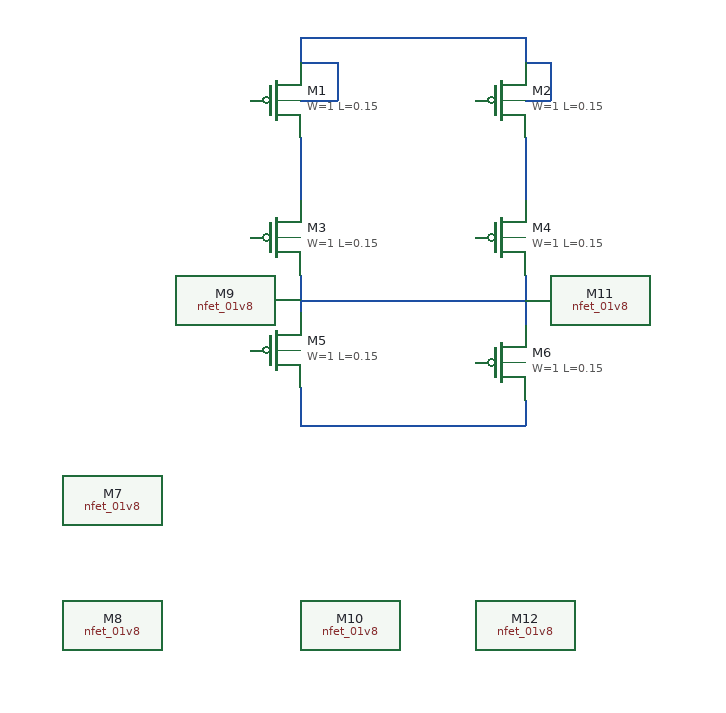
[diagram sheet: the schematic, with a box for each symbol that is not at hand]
v {xschem version=3.1.0 file_version=1.2
}
G {}
K {}
V {}
S {}
E {}
N 2750 -1520 2750 -1500 {}
N 2750 -1520 2930 -1520 {}
N 2930 -1520 2930 -1500 {}
N 2750 -1440 2750 -1400 {}
N 2750 -1400 2750 -1390 {}
N 2930 -1440 2930 -1390 {}
N 2750 -1330 2750 -1300 {}
N 2930 -1330 2930 -1290 {}
N 2930 -1230 2930 -1210 {}
N 2750 -1210 2930 -1210 {}
N 2750 -1240 2750 -1210 {}
N 2750 -1310 2930 -1310 {}
N 2750 -1470 2780 -1470 {}
N 2780 -1500 2780 -1470 {}
N 2750 -1500 2780 -1500 {}
N 2930 -1470 2950 -1470 {}
N 2950 -1500 2950 -1470 {}
N 2930 -1500 2950 -1500 {}
C {sky130_fd_pr/pfet_01v8.sym} 2730 -1470 0 0 {name=M1
L=0.15
W=1
nf=1
mult=1
ad="'int((nf+1)/2) * W/nf * 0.29'" 
pd="'2*int((nf+1)/2) * (W/nf + 0.29)'"
as="'int((nf+2)/2) * W/nf * 0.29'" 
ps="'2*int((nf+2)/2) * (W/nf + 0.29)'"
nrd="'0.29 / W'" nrs="'0.29 / W'"
sa=0 sb=0 sd=0
model=pfet_01v8
spiceprefix=X
}
C {sky130_fd_pr/pfet_01v8.sym} 2910 -1470 0 0 {name=M2
L=0.15
W=1
nf=1
mult=1
ad="'int((nf+1)/2) * W/nf * 0.29'" 
pd="'2*int((nf+1)/2) * (W/nf + 0.29)'"
as="'int((nf+2)/2) * W/nf * 0.29'" 
ps="'2*int((nf+2)/2) * (W/nf + 0.29)'"
nrd="'0.29 / W'" nrs="'0.29 / W'"
sa=0 sb=0 sd=0
model=pfet_01v8
spiceprefix=X
}
C {sky130_fd_pr/pfet_01v8.sym} 2730 -1360 0 0 {name=M3
L=0.15
W=1
nf=1
mult=1
ad="'int((nf+1)/2) * W/nf * 0.29'" 
pd="'2*int((nf+1)/2) * (W/nf + 0.29)'"
as="'int((nf+2)/2) * W/nf * 0.29'" 
ps="'2*int((nf+2)/2) * (W/nf + 0.29)'"
nrd="'0.29 / W'" nrs="'0.29 / W'"
sa=0 sb=0 sd=0
model=pfet_01v8
spiceprefix=X
}
C {sky130_fd_pr/pfet_01v8.sym} 2910 -1360 0 0 {name=M4
L=0.15
W=1
nf=1
mult=1
ad="'int((nf+1)/2) * W/nf * 0.29'" 
pd="'2*int((nf+1)/2) * (W/nf + 0.29)'"
as="'int((nf+2)/2) * W/nf * 0.29'" 
ps="'2*int((nf+2)/2) * (W/nf + 0.29)'"
nrd="'0.29 / W'" nrs="'0.29 / W'"
sa=0 sb=0 sd=0
model=pfet_01v8
spiceprefix=X
}
C {sky130_fd_pr/pfet_01v8.sym} 2730 -1270 0 0 {name=M5
L=0.15
W=1
nf=1
mult=1
ad="'int((nf+1)/2) * W/nf * 0.29'" 
pd="'2*int((nf+1)/2) * (W/nf + 0.29)'"
as="'int((nf+2)/2) * W/nf * 0.29'" 
ps="'2*int((nf+2)/2) * (W/nf + 0.29)'"
nrd="'0.29 / W'" nrs="'0.29 / W'"
sa=0 sb=0 sd=0
model=pfet_01v8
spiceprefix=X
}
C {sky130_fd_pr/pfet_01v8.sym} 2910 -1260 0 0 {name=M6
L=0.15
W=1
nf=1
mult=1
ad="'int((nf+1)/2) * W/nf * 0.29'" 
pd="'2*int((nf+1)/2) * (W/nf + 0.29)'"
as="'int((nf+2)/2) * W/nf * 0.29'" 
ps="'2*int((nf+2)/2) * (W/nf + 0.29)'"
nrd="'0.29 / W'" nrs="'0.29 / W'"
sa=0 sb=0 sd=0
model=pfet_01v8
spiceprefix=X
}
C {sky130_fd_pr/nfet_01v8.sym} 2600 -1150 0 0 {name=M7
L=0.15
W=1
nf=1 
mult=1
ad="'int((nf+1)/2) * W/nf * 0.29'" 
pd="'2*int((nf+1)/2) * (W/nf + 0.29)'"
as="'int((nf+2)/2) * W/nf * 0.29'" 
ps="'2*int((nf+2)/2) * (W/nf + 0.29)'"
nrd="'0.29 / W'" nrs="'0.29 / W'"
sa=0 sb=0 sd=0
model=nfet_01v8
spiceprefix=X
}
C {sky130_fd_pr/nfet_01v8.sym} 2600 -1050 0 0 {name=M8
L=0.15
W=1
nf=1 
mult=1
ad="'int((nf+1)/2) * W/nf * 0.29'" 
pd="'2*int((nf+1)/2) * (W/nf + 0.29)'"
as="'int((nf+2)/2) * W/nf * 0.29'" 
ps="'2*int((nf+2)/2) * (W/nf + 0.29)'"
nrd="'0.29 / W'" nrs="'0.29 / W'"
sa=0 sb=0 sd=0
model=nfet_01v8
spiceprefix=X
}
C {sky130_fd_pr/nfet_01v8.sym} 2790 -1150 0 0 {name=M9
L=0.15
W=1
nf=1 
mult=1
ad="'int((nf+1)/2) * W/nf * 0.29'" 
pd="'2*int((nf+1)/2) * (W/nf + 0.29)'"
as="'int((nf+2)/2) * W/nf * 0.29'" 
ps="'2*int((nf+2)/2) * (W/nf + 0.29)'"
nrd="'0.29 / W'" nrs="'0.29 / W'"
sa=0 sb=0 sd=0
model=nfet_01v8
spiceprefix=X
}
C {sky130_fd_pr/nfet_01v8.sym} 2790 -1050 0 0 {name=M10
L=0.15
W=1
nf=1 
mult=1
ad="'int((nf+1)/2) * W/nf * 0.29'" 
pd="'2*int((nf+1)/2) * (W/nf + 0.29)'"
as="'int((nf+2)/2) * W/nf * 0.29'" 
ps="'2*int((nf+2)/2) * (W/nf + 0.29)'"
nrd="'0.29 / W'" nrs="'0.29 / W'"
sa=0 sb=0 sd=0
model=nfet_01v8
spiceprefix=X
}
C {sky130_fd_pr/nfet_01v8.sym} 2940 -1150 0 0 {name=M11
L=0.15
W=1
nf=1 
mult=1
ad="'int((nf+1)/2) * W/nf * 0.29'" 
pd="'2*int((nf+1)/2) * (W/nf + 0.29)'"
as="'int((nf+2)/2) * W/nf * 0.29'" 
ps="'2*int((nf+2)/2) * (W/nf + 0.29)'"
nrd="'0.29 / W'" nrs="'0.29 / W'"
sa=0 sb=0 sd=0
model=nfet_01v8
spiceprefix=X
}
C {sky130_fd_pr/nfet_01v8.sym} 2930 -1050 0 0 {name=M12
L=0.15
W=1
nf=1 
mult=1
ad="'int((nf+1)/2) * W/nf * 0.29'" 
pd="'2*int((nf+1)/2) * (W/nf + 0.29)'"
as="'int((nf+2)/2) * W/nf * 0.29'" 
ps="'2*int((nf+2)/2) * (W/nf + 0.29)'"
nrd="'0.29 / W'" nrs="'0.29 / W'"
sa=0 sb=0 sd=0
model=nfet_01v8
spiceprefix=X
}
